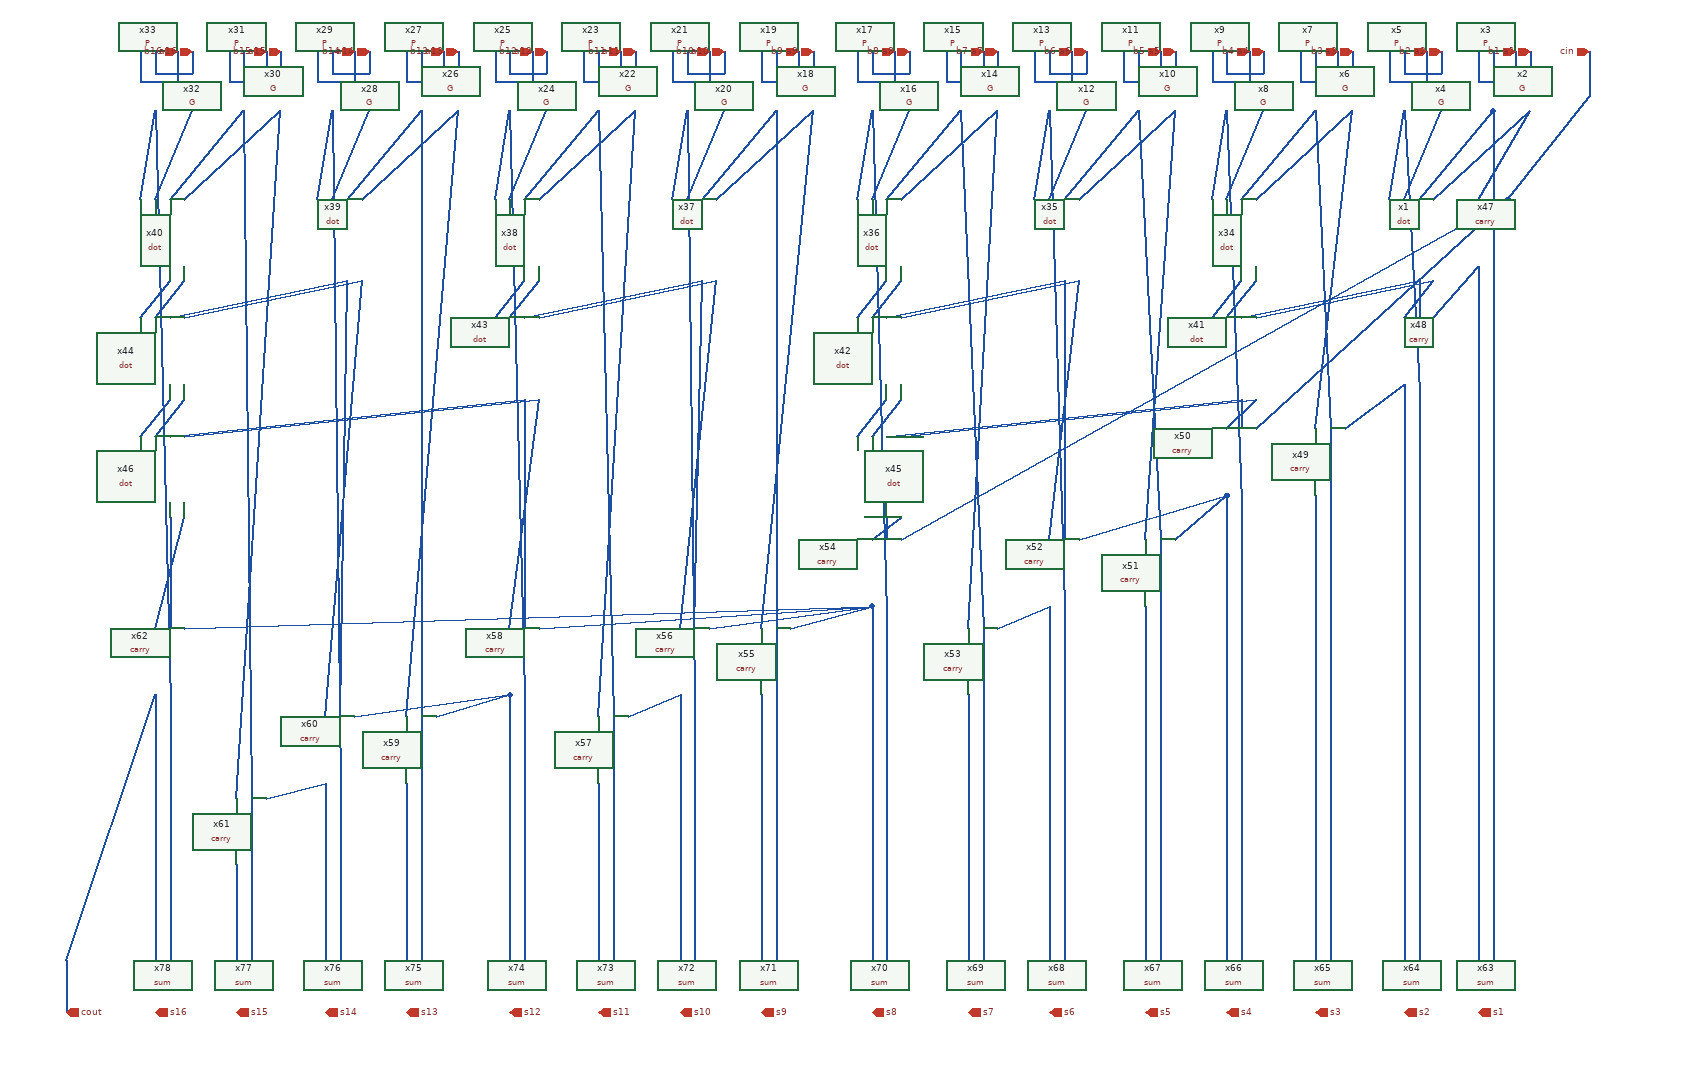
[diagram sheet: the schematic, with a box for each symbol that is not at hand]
v {xschem version=3.4.6 file_version=1.2}
G {}
K {}
V {}
S {}
E {}
N 790 90 890 -30 {lab=#net1}
N 810 90 940 -30 {lab=#net2}
N 750 90 770 -30 {lab=#net3}
N 770 90 820 -30 {lab=#net4}
N 550 90 650 -30 {lab=#net5}
N 570 90 700 -30 {lab=#net6}
N 510 90 530 -30 {lab=#net7}
N 530 90 580 -30 {lab=#net8}
N 310 90 410 -30 {lab=#net9}
N 330 90 460 -30 {lab=#net10}
N 270 90 290 -30 {lab=#net11}
N 290 90 340 -30 {lab=#net12}
N 70 90 170 -30 {lab=#net13}
N 90 90 220 -30 {lab=#net14}
N 30 90 50 -30 {lab=#net15}
N 50 90 100 -30 {lab=#net16}
N -180 90 -80 -30 {lab=#net17}
N -160 90 -30 -30 {lab=#net18}
N -220 90 -200 -30 {lab=#net19}
N -200 90 -150 -30 {lab=#net20}
N -420 90 -320 -30 {lab=#net21}
N -400 90 -270 -30 {lab=#net22}
N -460 90 -440 -30 {lab=#net23}
N -440 90 -390 -30 {lab=#net24}
N -660 90 -560 -30 {lab=#net25}
N -640 90 -510 -30 {lab=#net26}
N -700 90 -680 -30 {lab=#net27}
N -680 90 -630 -30 {lab=#net28}
N -900 90 -800 -30 {lab=#net29}
N -880 90 -750 -30 {lab=#net30}
N -940 90 -920 -30 {lab=#net31}
N -920 90 -870 -30 {lab=#net32}
N 510 250 550 200 {lab=#net33}
N 530 250 570 200 {lab=#net34}
N 550 250 790 200 {lab=#net35}
N 570 250 810 200 {lab=#net36}
N 30 250 70 200 {lab=#net37}
N 50 250 90 200 {lab=#net38}
N 70 250 310 200 {lab=#net39}
N 90 250 330 200 {lab=#net40}
N -460 250 -420 200 {lab=#net41}
N -440 250 -400 200 {lab=#net42}
N -420 250 -180 200 {lab=#net43}
N -400 250 -160 200 {lab=#net44}
N -940 250 -900 200 {lab=#net45}
N -920 250 -880 200 {lab=#net46}
N -900 250 -660 200 {lab=#net47}
N -880 250 -640 200 {lab=#net48}
N -940 410 -900 360 {lab=#net49}
N -920 410 -880 360 {lab=#net50}
N -900 410 -420 360 {lab=#net51}
N -880 410 -400 360 {lab=#net52}
N 30 410 70 360 {lab=#net53}
N 50 410 90 360 {lab=#net54}
N 70 410 550 360 {lab=#net55}
N 90 410 570 360 {lab=#net56}
N 890 -30 890 90 {lab=#net1}
N 870 90 940 -30 {lab=#net2}
N 790 200 790 250 {lab=#net35}
N 770 250 810 200 {lab=#net36}
N 650 -30 670 400 {lab=#net5}
N 650 400 700 -30 {lab=#net6}
N 550 360 550 400 {lab=#net55}
N 530 400 570 360 {lab=#net56}
N 310 200 310 550 {lab=#net39}
N 290 550 330 200 {lab=#net40}
N 410 -30 440 550 {lab=#net9}
N 420 550 460 -30 {lab=#net10}
N 810 250 870 180 {lab=#net57}
N 690 400 770 340 {lab=#net58}
N 460 550 530 490 {lab=#net59}
N 330 550 530 490 {lab=#net59}
N 220 670 290 640 {lab=#net60}
N -60 670 50 640 {lab=#net61}
N -170 670 50 640 {lab=#net61}
N -400 670 50 640 {lab=#net61}
N -880 670 50 640 {lab=#net61}
N -280 790 -210 760 {lab=#net62}
N -540 790 -440 760 {lab=#net63}
N -650 790 -440 760 {lab=#net63}
N -770 900 -690 880 {lab=#net64}
N -800 -30 -790 900 {lab=#net29}
N -810 900 -750 -30 {lab=#net30}
N -690 790 -640 200 {lab=#net48}
N -670 790 -660 200 {lab=#net47}
N -580 790 -510 -30 {lab=#net26}
N -560 -30 -560 790 {lab=#net25}
N -440 670 -400 360 {lab=#net52}
N -420 360 -420 670 {lab=#net51}
N -320 790 -270 -30 {lab=#net22}
N -320 -30 -300 790 {lab=#net21}
N -210 670 -160 200 {lab=#net44}
N -190 670 -180 200 {lab=#net43}
N -100 670 -30 -30 {lab=#net18}
N -80 -30 -80 670 {lab=#net17}
N 70 520 70 550 {lab=#net65}
N 50 550 90 520 {lab=#net66}
N 180 670 220 -30 {lab=#net14}
N 170 -30 200 670 {lab=#net13}
N -920 670 -880 520 {lab=#net67}
N -900 520 -900 670 {lab=#net68}
N 90 550 910 90 {lab=cin}
N 570 400 910 90 {lab=cin}
N 910 90 1020 -50 {lab=cin}
N 1020 -110 1020 -50 {lab=cin}
N -920 760 -920 1120 {lab=cout}
N -810 1000 -810 1120 {lab=#net69}
N -690 880 -690 1120 {lab=#net64}
N -580 880 -580 1120 {lab=#net70}
N -440 760 -440 1120 {lab=#net63}
N -320 880 -320 1120 {lab=#net71}
N -210 760 -210 1120 {lab=#net62}
N -100 760 -100 1120 {lab=#net72}
N 50 640 50 1120 {lab=#net61}
N 180 760 180 1120 {lab=#net73}
N 290 640 290 1120 {lab=#net60}
N 420 640 420 1120 {lab=#net74}
N 530 490 530 1120 {lab=#net59}
N 650 490 650 1120 {lab=#net75}
N 770 340 770 1110 {lab=#net58}
N 770 1110 770 1120 {lab=#net58}
N 870 180 870 1120 {lab=#net57}
N 890 -30 890 1120 {lab=#net1}
N 770 -30 790 350 {lab=#net3}
N 790 350 790 1120 {lab=#net3}
N 670 400 670 1120 {lab=#net5}
N 530 -30 550 500 {lab=#net7}
N 550 500 550 1120 {lab=#net7}
N 440 550 440 1120 {lab=#net9}
N 290 -30 310 640 {lab=#net11}
N 310 640 310 1120 {lab=#net11}
N 200 670 200 1120 {lab=#net13}
N 50 -30 70 650 {lab=#net15}
N 70 650 70 1120 {lab=#net15}
N -80 670 -80 1120 {lab=#net17}
N -200 -30 -190 770 {lab=#net19}
N -190 770 -190 1120 {lab=#net19}
N -300 790 -300 1120 {lab=#net21}
N -440 -30 -420 760 {lab=#net23}
N -420 760 -420 1120 {lab=#net23}
N -560 790 -560 1120 {lab=#net25}
N -680 -30 -670 890 {lab=#net27}
N -670 890 -670 1120 {lab=#net27}
N -790 900 -790 1120 {lab=#net29}
N -920 -30 -900 770 {lab=#net31}
N -900 770 -900 1120 {lab=#net31}
N 940 -110 940 -80 {lab=a1}
N 890 -80 940 -80 {lab=a1}
N 890 -110 890 -80 {lab=a1}
N 920 -110 920 -70 {lab=b1}
N 870 -70 920 -70 {lab=b1}
N 870 -110 870 -70 {lab=b1}
N 820 -110 820 -80 {lab=a2}
N 770 -80 820 -80 {lab=a2}
N 770 -110 770 -80 {lab=a2}
N 800 -110 800 -70 {lab=b2}
N 750 -70 800 -70 {lab=b2}
N 750 -110 750 -70 {lab=b2}
N 700 -110 700 -80 {lab=a3}
N 650 -80 700 -80 {lab=a3}
N 650 -110 650 -80 {lab=a3}
N 680 -110 680 -70 {lab=b3}
N 630 -70 680 -70 {lab=b3}
N 630 -110 630 -70 {lab=b3}
N 580 -110 580 -80 {lab=a4}
N 530 -80 580 -80 {lab=a4}
N 530 -110 530 -80 {lab=a4}
N 560 -110 560 -70 {lab=b4}
N 510 -70 560 -70 {lab=b4}
N 510 -110 510 -70 {lab=b4}
N 460 -110 460 -80 {lab=a5}
N 410 -80 460 -80 {lab=a5}
N 410 -110 410 -80 {lab=a5}
N 440 -110 440 -70 {lab=b5}
N 390 -70 440 -70 {lab=b5}
N 390 -110 390 -70 {lab=b5}
N 340 -110 340 -80 {lab=a6}
N 290 -80 340 -80 {lab=a6}
N 290 -110 290 -80 {lab=a6}
N 320 -110 320 -70 {lab=b6}
N 270 -70 320 -70 {lab=b6}
N 270 -110 270 -70 {lab=b6}
N 220 -110 220 -80 {lab=a7}
N 170 -80 220 -80 {lab=a7}
N 170 -110 170 -80 {lab=a7}
N 200 -110 200 -70 {lab=b7}
N 150 -70 200 -70 {lab=b7}
N 150 -110 150 -70 {lab=b7}
N 100 -110 100 -80 {lab=a8}
N 50 -80 100 -80 {lab=a8}
N 50 -110 50 -80 {lab=a8}
N 80 -110 80 -70 {lab=b8}
N 30 -70 80 -70 {lab=b8}
N 30 -110 30 -70 {lab=b8}
N -30 -110 -30 -80 {lab=a9}
N -80 -80 -30 -80 {lab=a9}
N -80 -110 -80 -80 {lab=a9}
N -50 -110 -50 -70 {lab=b9}
N -100 -70 -50 -70 {lab=b9}
N -100 -110 -100 -70 {lab=b9}
N -150 -110 -150 -80 {lab=a10}
N -200 -80 -150 -80 {lab=a10}
N -200 -110 -200 -80 {lab=a10}
N -170 -110 -170 -70 {lab=b10}
N -220 -70 -170 -70 {lab=b10}
N -220 -110 -220 -70 {lab=b10}
N -270 -110 -270 -80 {lab=a11}
N -320 -80 -270 -80 {lab=a11}
N -320 -110 -320 -80 {lab=a11}
N -290 -110 -290 -70 {lab=b11}
N -340 -70 -290 -70 {lab=b11}
N -340 -110 -340 -70 {lab=b11}
N -390 -110 -390 -80 {lab=a12}
N -440 -80 -390 -80 {lab=a12}
N -440 -110 -440 -80 {lab=a12}
N -410 -110 -410 -70 {lab=b12}
N -460 -70 -410 -70 {lab=b12}
N -460 -110 -460 -70 {lab=b12}
N -510 -110 -510 -80 {lab=a13}
N -560 -80 -510 -80 {lab=a13}
N -560 -110 -560 -80 {lab=a13}
N -530 -110 -530 -70 {lab=b13}
N -580 -70 -530 -70 {lab=b13}
N -580 -110 -580 -70 {lab=b13}
N -630 -110 -630 -80 {lab=a14}
N -680 -80 -630 -80 {lab=a14}
N -680 -110 -680 -80 {lab=a14}
N -650 -110 -650 -70 {lab=b14}
N -700 -70 -650 -70 {lab=b14}
N -700 -110 -700 -70 {lab=b14}
N -750 -110 -750 -80 {lab=a15}
N -800 -80 -750 -80 {lab=a15}
N -800 -110 -800 -80 {lab=a15}
N -770 -110 -770 -70 {lab=b15}
N -820 -70 -770 -70 {lab=b15}
N -820 -110 -820 -70 {lab=b15}
N -870 -110 -870 -80 {lab=a16}
N -920 -80 -870 -80 {lab=a16}
N -920 -110 -920 -80 {lab=a16}
N -890 -110 -890 -70 {lab=b16}
N -940 -70 -890 -70 {lab=b16}
N -940 -110 -940 -70 {lab=b16}
N -1040 1120 -920 760 {lab=cout}
N -1040 1120 -1040 1190 {lab=cout}
N -810 990 -810 1000 {lab=#net69}
C {dot.sym} 780 150 1 0 {name=x1}
C {G.sym} 930 -70 1 0 {name=x2}
C {P.sym} 880 -70 1 0 {name=x3}
C {G.sym} 810 -70 1 0 {name=x4}
C {P.sym} 760 -70 1 0 {name=x5}
C {G.sym} 690 -70 1 0 {name=x6}
C {P.sym} 640 -70 1 0 {name=x7}
C {G.sym} 570 -70 1 0 {name=x8}
C {P.sym} 520 -70 1 0 {name=x9}
C {G.sym} 450 -70 1 0 {name=x10}
C {P.sym} 400 -70 1 0 {name=x11}
C {G.sym} 330 -70 1 0 {name=x12}
C {P.sym} 280 -70 1 0 {name=x13}
C {G.sym} 210 -70 1 0 {name=x14}
C {P.sym} 160 -70 1 0 {name=x15}
C {G.sym} 90 -70 1 0 {name=x16}
C {P.sym} 40 -70 1 0 {name=x17}
C {G.sym} -40 -70 1 0 {name=x18}
C {P.sym} -90 -70 1 0 {name=x19}
C {G.sym} -160 -70 1 0 {name=x20}
C {P.sym} -210 -70 1 0 {name=x21}
C {G.sym} -280 -70 1 0 {name=x22}
C {P.sym} -330 -70 1 0 {name=x23}
C {G.sym} -400 -70 1 0 {name=x24}
C {P.sym} -450 -70 1 0 {name=x25}
C {G.sym} -520 -70 1 0 {name=x26}
C {P.sym} -570 -70 1 0 {name=x27}
C {G.sym} -640 -70 1 0 {name=x28}
C {P.sym} -690 -70 1 0 {name=x29}
C {G.sym} -760 -70 1 0 {name=x30}
C {P.sym} -810 -70 1 0 {name=x31}
C {G.sym} -880 -70 1 0 {name=x32}
C {P.sym} -930 -70 1 0 {name=x33}
C {dot.sym} 540 150 1 0 {name=x34}
C {dot.sym} 300 150 1 0 {name=x35}
C {dot.sym} 60 150 1 0 {name=x36}
C {dot.sym} -190 150 1 0 {name=x37}
C {dot.sym} -430 150 1 0 {name=x38}
C {dot.sym} -670 150 1 0 {name=x39}
C {dot.sym} -910 150 1 0 {name=x40}
C {dot.sym} 540 310 1 0 {name=x41}
C {dot.sym} 60 310 1 0 {name=x42}
C {dot.sym} -430 310 1 0 {name=x43}
C {dot.sym} -910 310 1 0 {name=x44}
C {dot.sym} 60 470 1 0 {name=x45}
C {dot.sym} -910 470 1 0 {name=x46}
C {carry.sym} 890 140 3 1 {name=x47}
C {carry.sym} 790 300 3 1 {name=x48}
C {carry.sym} 670 450 3 1 {name=x49}
C {carry.sym} 550 450 3 1 {name=x50}
C {carry.sym} 440 600 3 1 {name=x51}
C {carry.sym} 310 600 3 1 {name=x52}
C {carry.sym} 200 720 3 1 {name=x53}
C {carry.sym} 70 600 3 1 {name=x54}
C {carry.sym} -80 720 3 1 {name=x55}
C {carry.sym} -190 720 3 1 {name=x56}
C {carry.sym} -300 840 3 1 {name=x57}
C {carry.sym} -420 720 3 1 {name=x58}
C {carry.sym} -560 840 3 1 {name=x59}
C {carry.sym} -670 840 3 1 {name=x60}
C {carry.sym} -790 950 3 1 {name=x61}
C {carry.sym} -900 720 3 1 {name=x62}
C {sum.sym} 880 1150 3 1 {name=x63}
C {sum.sym} 780 1150 3 1 {name=x64}
C {sum.sym} 660 1150 3 1 {name=x65}
C {sum.sym} 540 1150 3 1 {name=x66}
C {sum.sym} 430 1150 3 1 {name=x67}
C {sum.sym} 300 1150 3 1 {name=x68}
C {sum.sym} 190 1150 3 1 {name=x69}
C {sum.sym} 60 1150 3 1 {name=x70}
C {sum.sym} -90 1150 3 1 {name=x71}
C {sum.sym} -200 1150 3 1 {name=x72}
C {sum.sym} -310 1150 3 1 {name=x73}
C {sum.sym} -430 1150 3 1 {name=x74}
C {sum.sym} -570 1150 3 1 {name=x75}
C {sum.sym} -680 1150 3 1 {name=x76}
C {sum.sym} -800 1150 3 1 {name=x77}
C {sum.sym} -910 1150 3 1 {name=x78}
C {ipin.sym} -890 -110 1 0 {name=p3 lab=b16}
C {ipin.sym} -870 -110 1 0 {name=p4 lab=a16}
C {ipin.sym} -770 -110 1 0 {name=p7 lab=b15}
C {ipin.sym} -750 -110 1 0 {name=p8 lab=a15}
C {ipin.sym} -650 -110 1 0 {name=p11 lab=b14}
C {ipin.sym} -630 -110 1 0 {name=p12 lab=a14}
C {ipin.sym} -530 -110 1 0 {name=p15 lab=b13}
C {ipin.sym} -510 -110 1 0 {name=p16 lab=a13}
C {ipin.sym} -410 -110 1 0 {name=p19 lab=b12}
C {ipin.sym} -390 -110 1 0 {name=p20 lab=a12}
C {ipin.sym} -290 -110 1 0 {name=p23 lab=b11}
C {ipin.sym} -270 -110 1 0 {name=p24 lab=a11}
C {ipin.sym} -170 -110 1 0 {name=p27 lab=b10}
C {ipin.sym} -150 -110 1 0 {name=p28 lab=a10}
C {ipin.sym} -50 -110 1 0 {name=p31 lab=b9}
C {ipin.sym} -30 -110 1 0 {name=p32 lab=a9}
C {ipin.sym} 80 -110 1 0 {name=p35 lab=b8}
C {ipin.sym} 100 -110 1 0 {name=p36 lab=a8}
C {ipin.sym} 200 -110 1 0 {name=p39 lab=b7}
C {ipin.sym} 220 -110 1 0 {name=p40 lab=a7}
C {ipin.sym} 320 -110 1 0 {name=p43 lab=b6}
C {ipin.sym} 340 -110 1 0 {name=p44 lab=a6}
C {ipin.sym} 440 -110 1 0 {name=p47 lab=b5}
C {ipin.sym} 460 -110 1 0 {name=p48 lab=a5}
C {ipin.sym} 560 -110 1 0 {name=p51 lab=b4}
C {ipin.sym} 580 -110 1 0 {name=p52 lab=a4}
C {ipin.sym} 680 -110 1 0 {name=p55 lab=b3}
C {ipin.sym} 700 -110 1 0 {name=p56 lab=a3}
C {ipin.sym} 800 -110 1 0 {name=p59 lab=b2}
C {ipin.sym} 820 -110 1 0 {name=p60 lab=a2}
C {ipin.sym} 920 -110 1 0 {name=p63 lab=b1}
C {ipin.sym} 940 -110 1 0 {name=p64 lab=a1}
C {ipin.sym} 1020 -110 1 0 {name=p65 lab=cin}
C {opin.sym} 870 1190 1 0 {name=p1 lab=s1}
C {opin.sym} 770 1190 1 0 {name=p2 lab=s2}
C {opin.sym} 650 1190 1 0 {name=p5 lab=s3}
C {opin.sym} 530 1190 1 0 {name=p6 lab=s4}
C {opin.sym} 420 1190 1 0 {name=p9 lab=s5}
C {opin.sym} 290 1190 1 0 {name=p10 lab=s6}
C {opin.sym} 180 1190 1 0 {name=p13 lab=s7}
C {opin.sym} 50 1190 1 0 {name=p14 lab=s8}
C {opin.sym} -100 1190 1 0 {name=p17 lab=s9}
C {opin.sym} -210 1190 1 0 {name=p18 lab=s10}
C {opin.sym} -320 1190 1 0 {name=p21 lab=s11}
C {opin.sym} -440 1190 1 0 {name=p22 lab=s12}
C {opin.sym} -580 1190 1 0 {name=p25 lab=s13}
C {opin.sym} -690 1190 1 0 {name=p26 lab=s14}
C {opin.sym} -810 1190 1 0 {name=p29 lab=s15}
C {opin.sym} -920 1190 1 0 {name=p30 lab=s16}
C {opin.sym} -1040 1190 1 0 {name=p33 lab=cout}
